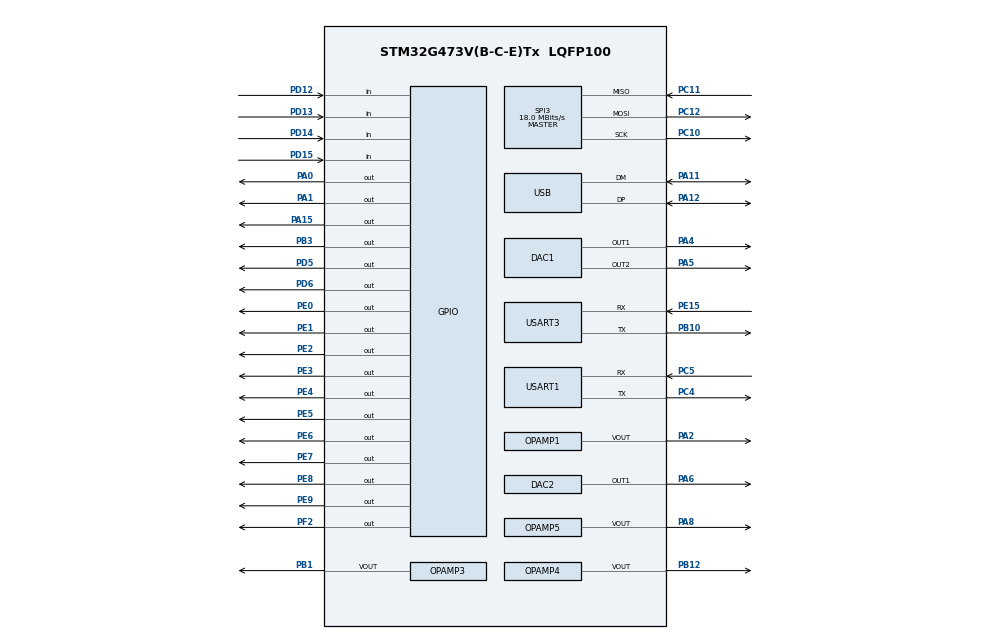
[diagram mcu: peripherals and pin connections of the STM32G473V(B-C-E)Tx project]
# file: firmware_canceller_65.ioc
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DAC1.DAC_Channel-DAC_OUT2=DAC_CHANNEL_2
DAC3.DAC_Channel-DAC_OUT2_Int=DAC_CHANNEL_2
DAC4.DAC_Channel-DAC_OUT2_Int=DAC_CHANNEL_2
Mcu.Family=STM32G4
Mcu.Name=STM32G473V(B-C-E)Tx
Mcu.Package=LQFP100
NVIC.PriorityGroup=NVIC_PRIORITYGROUP_4
NVIC.USB_LP_IRQn=true\:0\:0\:false\:false\:true\:false\:true\:true
PA0.Signal=GPIO_Output
PA1.Signal=GPIO_Output
PA11.Mode=Device
PA11.Signal=USB_DM
PA12.Mode=Device
PA12.Signal=USB_DP
PA13.Mode=Serial_Wire
PA13.Signal=SYS_JTMS-SWDIO
PA14.Mode=Serial_Wire
PA14.Signal=SYS_JTCK-SWCLK
PA15.Signal=GPIO_Output
PA2.Mode=Follower-DAC_OUT2-INP
PA2.Signal=OPAMP1_VOUT
PA4.Signal=COMP_DAC11_group
PA5.Signal=COMP_DAC12_group
PA6.Signal=COMP_DAC21_group
PA8.Mode=Follower-DAC_OUT2-INP
PA8.Signal=OPAMP5_VOUT
PB1.Mode=Follower-DAC_OUT2-INP
PB1.Signal=OPAMP3_VOUT
PB10.Mode=Asynchronous
PB10.Signal=USART3_TX
PB12.Mode=Follower-DAC_OUT2-INP
PB12.Signal=OPAMP4_VOUT
PB3.Signal=GPIO_Output
PC10.Mode=Full_Duplex_Master
PC10.Signal=SPI3_SCK
PC11.Mode=Full_Duplex_Master
PC11.Signal=SPI3_MISO
PC12.Mode=Full_Duplex_Master
PC12.Signal=SPI3_MOSI
PC4.Mode=Asynchronous
PC4.Signal=USART1_TX
PC5.Mode=Asynchronous
PC5.Signal=USART1_RX
PD12.GPIO_PuPd=GPIO_PULLUP
PD12.Signal=GPIO_Input
PD13.GPIO_PuPd=GPIO_PULLUP
PD13.Signal=GPIO_Input
PD14.GPIO_PuPd=GPIO_PULLUP
PD14.Signal=GPIO_Input
PD15.GPIO_PuPd=GPIO_PULLUP
PD15.Signal=GPIO_Input
PD5.Signal=GPIO_Output
PD6.Signal=GPIO_Output
PE0.Signal=GPIO_Output
PE1.Signal=GPIO_Output
PE15.Mode=Asynchronous
PE15.Signal=USART3_RX
PE2.Signal=GPIO_Output
PE3.Signal=GPIO_Output
PE4.Signal=GPIO_Output
PE5.Signal=GPIO_Output
PE6.Signal=GPIO_Output
PE7.Signal=GPIO_Output
PE8.Signal=GPIO_Output
PE9.Signal=GPIO_Output
PF2.Signal=GPIO_Output
ProjectManager.HeapSize=0x200
ProjectManager.StackSize=0x400
ProjectManager.TargetToolchain=MDK-ARM V5.32
RCC.ADC12Freq_Value=144000000
RCC.ADC345Freq_Value=144000000
RCC.AHBFreq_Value=144000000
RCC.APB1Freq_Value=144000000
RCC.APB1TimFreq_Value=144000000
RCC.APB2Freq_Value=144000000
RCC.APB2TimFreq_Value=144000000
RCC.CK48CLockSelection=RCC_USBCLKSOURCE_HSI48
RCC.CortexFreq_Value=144000000
RCC.EXTERNAL_CLOCK_VALUE=12288000
RCC.HCLKFreq_Value=144000000
RCC.HSE_VALUE=12000000
RCC.HSI48_VALUE=48000000
RCC.HSI_VALUE=16000000
RCC.LSE_VALUE=32768
RCC.PLLN=18
RCC.SYSCLKFreq_VALUE=144000000
RCC.SYSCLKSource=RCC_SYSCLKSOURCE_PLLCLK
RCC.USBFreq_Value=48000000
RCC.VCOOutputFreq_Value=288000000
SH.COMP_DAC11_group.0=DAC1_OUT1,DAC_OUT1
SH.COMP_DAC12_group.0=DAC1_OUT2,DAC_OUT2
SH.COMP_DAC21_group.0=DAC2_OUT1,DAC_OUT1
SPI3.BaudRatePrescaler=SPI_BAUDRATEPRESCALER_8
SPI3.CLKPhase=SPI_PHASE_2EDGE
SPI3.CLKPolarity=SPI_POLARITY_LOW
SPI3.CalculateBaudRate=18.0 MBits/s
SPI3.DataSize=SPI_DATASIZE_8BIT
SPI3.Direction=SPI_DIRECTION_2LINES
SPI3.Mode=SPI_MODE_MASTER
SPI3.TIMode=SPI_TIMODE_DISABLE
SPI3.VirtualType=VM_MASTER
USART1.VirtualMode-Asynchronous=VM_ASYNC
USART3.VirtualMode-Asynchronous=VM_ASYNC
USB_DEVICE.CLASS_NAME_FS=CDC
USB_DEVICE.VirtualMode=Cdc
USB_DEVICE.VirtualModeFS=Cdc_FS
VP_DAC3_VS_DACI1.Mode=DAC_OUT1_Int
VP_DAC3_VS_DACI2.Mode=DAC_OUT2_Int
VP_DAC4_VS_DACI1.Mode=DAC_OUT1_Int
VP_DAC4_VS_DACI2.Mode=DAC_OUT2_Int
VP_SYS_VS_DBSignals.Mode=DisableDeadBatterySignals
VP_USB_DEVICE_VS_USB_DEVICE_CDC_FS.Mode=CDC_FS
board=custom

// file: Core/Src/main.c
/* USER CODE BEGIN Header */
/**
  ******************************************************************************
  * @file           : main.c
  * @brief          : Main program body
  ******************************************************************************
  * @attention
  *
  * Copyright (c) 2023 STMicroelectronics.
  * All rights reserved.
  *
  * This software is licensed under terms that can be found in the LICENSE file
  * in the root directory of this software component.
  * If no LICENSE file comes with this software, it is provided AS-IS.
  *
  ******************************************************************************
  */
/* USER CODE END Header */
#include "main.h"
#include "usb_device.h"

/* USER CODE BEGIN Includes */
#include "dacx0508.h"
#include "sic_control.h"
/* USER CODE END Includes */

DAC_HandleTypeDef hdac1;
DAC_HandleTypeDef hdac2;
DAC_HandleTypeDef hdac3;
DAC_HandleTypeDef hdac4;

OPAMP_HandleTypeDef hopamp1;
OPAMP_HandleTypeDef hopamp3;
OPAMP_HandleTypeDef hopamp4;
OPAMP_HandleTypeDef hopamp5;

SPI_HandleTypeDef hspi3;

UART_HandleTypeDef huart1;
UART_HandleTypeDef huart3;

/* USER CODE BEGIN PV */
tap_handle_type_def htap[5];
uint16_t id;
/* USER CODE END PV */

void SystemClock_Config(void);
static void MX_GPIO_Init(void);
static void MX_DAC1_Init(void);
static void MX_DAC2_Init(void);
static void MX_DAC3_Init(void);
static void MX_DAC4_Init(void);
static void MX_OPAMP1_Init(void);
static void MX_OPAMP3_Init(void);
static void MX_OPAMP4_Init(void);
static void MX_OPAMP5_Init(void);
static void MX_SPI3_Init(void);
static void MX_USART1_UART_Init(void);
static void MX_USART3_UART_Init(void);
/* USER CODE BEGIN PFP */
static void sic_init(void);
/* USER CODE END PFP */

int main(void)
{

  /* MCU Configuration--------------------------------------------------------*/

  /* Reset of all peripherals, Initializes the Flash interface and the Systick. */
  HAL_Init();

  /* Configure the system clock */
  SystemClock_Config();

  /* Initialize all configured peripherals */
  MX_GPIO_Init();
  MX_DAC1_Init();
  MX_DAC2_Init();
  MX_DAC3_Init();
  MX_DAC4_Init();
  MX_OPAMP1_Init();
  MX_OPAMP3_Init();
  MX_OPAMP4_Init();
  MX_OPAMP5_Init();
  MX_SPI3_Init();
  MX_USART1_UART_Init();
  MX_USART3_UART_Init();
  MX_USB_Device_Init();
  /* USER CODE BEGIN 2 */
  dacx0508_init(&hspi3);
  sic_init();
  /* USER CODE END 2 */

  /* Infinite loop */
  while (1)
  {

    /* USER CODE BEGIN 3 */
//    if(HAL_GPIO_ReadPin(GPIOD,GPIO_PIN_12))
//      sic_amp_off();
//    else
//      sic_amp_on();

//    if(HAL_GPIO_ReadPin(GPIOD,GPIO_PIN_13))
//      sic_tap_off();
//    else
//      sic_tap_on();

    HAL_GPIO_TogglePin(GPIOA,GPIO_PIN_1);
    HAL_Delay(200);
  }
  /* USER CODE END 3 */
}

void SystemClock_Config(void)
{
  RCC_OscInitTypeDef RCC_OscInitStruct = {0};
  RCC_ClkInitTypeDef RCC_ClkInitStruct = {0};

  /** Configure the main internal regulator output voltage
  */
  HAL_PWREx_ControlVoltageScaling(PWR_REGULATOR_VOLTAGE_SCALE1_BOOST);

  /** Initializes the RCC Oscillators according to the specified parameters
  * in the RCC_OscInitTypeDef structure.
  */
  RCC_OscInitStruct.OscillatorType = RCC_OSCILLATORTYPE_HSI|RCC_OSCILLATORTYPE_HSI48;
  RCC_OscInitStruct.HSIState = RCC_HSI_ON;
  RCC_OscInitStruct.HSICalibrationValue = RCC_HSICALIBRATION_DEFAULT;
  RCC_OscInitStruct.HSI48State = RCC_HSI48_ON;
  RCC_OscInitStruct.PLL.PLLState = RCC_PLL_ON;
  RCC_OscInitStruct.PLL.PLLSource = RCC_PLLSOURCE_HSI;
  RCC_OscInitStruct.PLL.PLLM = RCC_PLLM_DIV1;
  RCC_OscInitStruct.PLL.PLLN = 20;
  RCC_OscInitStruct.PLL.PLLP = RCC_PLLP_DIV2;
  RCC_OscInitStruct.PLL.PLLQ = RCC_PLLQ_DIV2;
  RCC_OscInitStruct.PLL.PLLR = RCC_PLLR_DIV2;
  if (HAL_RCC_OscConfig(&RCC_OscInitStruct) != HAL_OK)
  {
    Error_Handler();
  }

  /** Initializes the CPU, AHB and APB buses clocks
  */
  RCC_ClkInitStruct.ClockType = RCC_CLOCKTYPE_HCLK|RCC_CLOCKTYPE_SYSCLK
                              |RCC_CLOCKTYPE_PCLK1|RCC_CLOCKTYPE_PCLK2;
  RCC_ClkInitStruct.SYSCLKSource = RCC_SYSCLKSOURCE_PLLCLK;
  RCC_ClkInitStruct.AHBCLKDivider = RCC_SYSCLK_DIV1;
  RCC_ClkInitStruct.APB1CLKDivider = RCC_HCLK_DIV1;
  RCC_ClkInitStruct.APB2CLKDivider = RCC_HCLK_DIV1;

  if (HAL_RCC_ClockConfig(&RCC_ClkInitStruct, FLASH_LATENCY_4) != HAL_OK)
  {
    Error_Handler();
  }
}

static void MX_DAC1_Init(void)
{

  DAC_ChannelConfTypeDef sConfig = {0};

  /** DAC Initialization
  */
  hdac1.Instance = DAC1;
  if (HAL_DAC_Init(&hdac1) != HAL_OK)
  {
    Error_Handler();
  }

  /** DAC channel OUT1 config
  */
  sConfig.DAC_HighFrequency = DAC_HIGH_FREQUENCY_INTERFACE_MODE_AUTOMATIC;
  sConfig.DAC_DMADoubleDataMode = DISABLE;
  sConfig.DAC_SignedFormat = DISABLE;
  sConfig.DAC_SampleAndHold = DAC_SAMPLEANDHOLD_DISABLE;
  sConfig.DAC_Trigger = DAC_TRIGGER_NONE;
  sConfig.DAC_Trigger2 = DAC_TRIGGER_NONE;
  sConfig.DAC_OutputBuffer = DAC_OUTPUTBUFFER_ENABLE;
  sConfig.DAC_ConnectOnChipPeripheral = DAC_CHIPCONNECT_EXTERNAL;
  sConfig.DAC_UserTrimming = DAC_TRIMMING_FACTORY;
  if (HAL_DAC_ConfigChannel(&hdac1, &sConfig, DAC_CHANNEL_1) != HAL_OK)
  {
    Error_Handler();
  }

  /** DAC channel OUT2 config
  */
  if (HAL_DAC_ConfigChannel(&hdac1, &sConfig, DAC_CHANNEL_2) != HAL_OK)
  {
    Error_Handler();
  }

}

static void MX_DAC2_Init(void)
{

  DAC_ChannelConfTypeDef sConfig = {0};

  /** DAC Initialization
  */
  hdac2.Instance = DAC2;
  if (HAL_DAC_Init(&hdac2) != HAL_OK)
  {
    Error_Handler();
  }

  /** DAC channel OUT1 config
  */
  sConfig.DAC_HighFrequency = DAC_HIGH_FREQUENCY_INTERFACE_MODE_AUTOMATIC;
  sConfig.DAC_DMADoubleDataMode = DISABLE;
  sConfig.DAC_SignedFormat = DISABLE;
  sConfig.DAC_SampleAndHold = DAC_SAMPLEANDHOLD_DISABLE;
  sConfig.DAC_Trigger = DAC_TRIGGER_NONE;
  sConfig.DAC_Trigger2 = DAC_TRIGGER_NONE;
  sConfig.DAC_OutputBuffer = DAC_OUTPUTBUFFER_ENABLE;
  sConfig.DAC_ConnectOnChipPeripheral = DAC_CHIPCONNECT_EXTERNAL;
  sConfig.DAC_UserTrimming = DAC_TRIMMING_FACTORY;
  if (HAL_DAC_ConfigChannel(&hdac2, &sConfig, DAC_CHANNEL_1) != HAL_OK)
  {
    Error_Handler();
  }

}

static void MX_DAC3_Init(void)
{

  DAC_ChannelConfTypeDef sConfig = {0};

  /** DAC Initialization
  */
  hdac3.Instance = DAC3;
  if (HAL_DAC_Init(&hdac3) != HAL_OK)
  {
    Error_Handler();
  }

  /** DAC channel OUT1 config
  */
  sConfig.DAC_HighFrequency = DAC_HIGH_FREQUENCY_INTERFACE_MODE_AUTOMATIC;
  sConfig.DAC_DMADoubleDataMode = DISABLE;
  sConfig.DAC_SignedFormat = DISABLE;
  sConfig.DAC_SampleAndHold = DAC_SAMPLEANDHOLD_DISABLE;
  sConfig.DAC_Trigger = DAC_TRIGGER_NONE;
  sConfig.DAC_Trigger2 = DAC_TRIGGER_NONE;
  sConfig.DAC_OutputBuffer = DAC_OUTPUTBUFFER_DISABLE;
  sConfig.DAC_ConnectOnChipPeripheral = DAC_CHIPCONNECT_INTERNAL;
  sConfig.DAC_UserTrimming = DAC_TRIMMING_FACTORY;
  if (HAL_DAC_ConfigChannel(&hdac3, &sConfig, DAC_CHANNEL_1) != HAL_OK)
  {
    Error_Handler();
  }

  /** DAC channel OUT2 config
  */
  if (HAL_DAC_ConfigChannel(&hdac3, &sConfig, DAC_CHANNEL_2) != HAL_OK)
  {
    Error_Handler();
  }

}

static void MX_DAC4_Init(void)
{

  DAC_ChannelConfTypeDef sConfig = {0};

  /** DAC Initialization
  */
  hdac4.Instance = DAC4;
  if (HAL_DAC_Init(&hdac4) != HAL_OK)
  {
    Error_Handler();
  }

  /** DAC channel OUT1 config
  */
  sConfig.DAC_HighFrequency = DAC_HIGH_FREQUENCY_INTERFACE_MODE_AUTOMATIC;
  sConfig.DAC_DMADoubleDataMode = DISABLE;
  sConfig.DAC_SignedFormat = DISABLE;
  sConfig.DAC_SampleAndHold = DAC_SAMPLEANDHOLD_DISABLE;
  sConfig.DAC_Trigger = DAC_TRIGGER_NONE;
  sConfig.DAC_Trigger2 = DAC_TRIGGER_NONE;
  sConfig.DAC_OutputBuffer = DAC_OUTPUTBUFFER_DISABLE;
  sConfig.DAC_ConnectOnChipPeripheral = DAC_CHIPCONNECT_INTERNAL;
  sConfig.DAC_UserTrimming = DAC_TRIMMING_FACTORY;
  if (HAL_DAC_ConfigChannel(&hdac4, &sConfig, DAC_CHANNEL_1) != HAL_OK)
  {
    Error_Handler();
  }

  /** DAC channel OUT2 config
  */
  if (HAL_DAC_ConfigChannel(&hdac4, &sConfig, DAC_CHANNEL_2) != HAL_OK)
  {
    Error_Handler();
  }

}

static void MX_OPAMP1_Init(void)
{

  hopamp1.Instance = OPAMP1;
  hopamp1.Init.PowerMode = OPAMP_POWERMODE_NORMALSPEED;
  hopamp1.Init.Mode = OPAMP_FOLLOWER_MODE;
  hopamp1.Init.NonInvertingInput = OPAMP_NONINVERTINGINPUT_DAC;
  hopamp1.Init.InternalOutput = DISABLE;
  hopamp1.Init.TimerControlledMuxmode = OPAMP_TIMERCONTROLLEDMUXMODE_DISABLE;
  hopamp1.Init.UserTrimming = OPAMP_TRIMMING_FACTORY;
  if (HAL_OPAMP_Init(&hopamp1) != HAL_OK)
  {
    Error_Handler();
  }

}

static void MX_OPAMP3_Init(void)
{

  hopamp3.Instance = OPAMP3;
  hopamp3.Init.PowerMode = OPAMP_POWERMODE_NORMALSPEED;
  hopamp3.Init.Mode = OPAMP_FOLLOWER_MODE;
  hopamp3.Init.NonInvertingInput = OPAMP_NONINVERTINGINPUT_DAC;
  hopamp3.Init.InternalOutput = DISABLE;
  hopamp3.Init.TimerControlledMuxmode = OPAMP_TIMERCONTROLLEDMUXMODE_DISABLE;
  hopamp3.Init.UserTrimming = OPAMP_TRIMMING_FACTORY;
  if (HAL_OPAMP_Init(&hopamp3) != HAL_OK)
  {
    Error_Handler();
  }

}

static void MX_OPAMP4_Init(void)
{

  hopamp4.Instance = OPAMP4;
  hopamp4.Init.PowerMode = OPAMP_POWERMODE_NORMALSPEED;
  hopamp4.Init.Mode = OPAMP_FOLLOWER_MODE;
  hopamp4.Init.NonInvertingInput = OPAMP_NONINVERTINGINPUT_DAC;
  hopamp4.Init.InternalOutput = DISABLE;
  hopamp4.Init.TimerControlledMuxmode = OPAMP_TIMERCONTROLLEDMUXMODE_DISABLE;
  hopamp4.Init.UserTrimming = OPAMP_TRIMMING_FACTORY;
  if (HAL_OPAMP_Init(&hopamp4) != HAL_OK)
  {
    Error_Handler();
  }

}

static void MX_OPAMP5_Init(void)
{

  hopamp5.Instance = OPAMP5;
  hopamp5.Init.PowerMode = OPAMP_POWERMODE_NORMALSPEED;
  hopamp5.Init.Mode = OPAMP_FOLLOWER_MODE;
  hopamp5.Init.NonInvertingInput = OPAMP_NONINVERTINGINPUT_DAC;
  hopamp5.Init.InternalOutput = DISABLE;
  hopamp5.Init.TimerControlledMuxmode = OPAMP_TIMERCONTROLLEDMUXMODE_DISABLE;
  hopamp5.Init.UserTrimming = OPAMP_TRIMMING_FACTORY;
  if (HAL_OPAMP_Init(&hopamp5) != HAL_OK)
  {
    Error_Handler();
  }

}

static void MX_SPI3_Init(void)
{

  /* SPI3 parameter configuration*/
  hspi3.Instance = SPI3;
  hspi3.Init.Mode = SPI_MODE_MASTER;
  hspi3.Init.Direction = SPI_DIRECTION_2LINES;
  hspi3.Init.DataSize = SPI_DATASIZE_8BIT;
  hspi3.Init.CLKPolarity = SPI_POLARITY_LOW;
  hspi3.Init.CLKPhase = SPI_PHASE_2EDGE;
  hspi3.Init.NSS = SPI_NSS_SOFT;
  hspi3.Init.BaudRatePrescaler = SPI_BAUDRATEPRESCALER_64;
  hspi3.Init.FirstBit = SPI_FIRSTBIT_MSB;
  hspi3.Init.TIMode = SPI_TIMODE_DISABLE;
  hspi3.Init.CRCCalculation = SPI_CRCCALCULATION_DISABLE;
  hspi3.Init.CRCPolynomial = 7;
  hspi3.Init.CRCLength = SPI_CRC_LENGTH_DATASIZE;
  hspi3.Init.NSSPMode = SPI_NSS_PULSE_DISABLE;
  if (HAL_SPI_Init(&hspi3) != HAL_OK)
  {
    Error_Handler();
  }

}

static void MX_USART1_UART_Init(void)
{

  huart1.Instance = USART1;
  huart1.Init.BaudRate = 115200;
  huart1.Init.WordLength = UART_WORDLENGTH_8B;
  huart1.Init.StopBits = UART_STOPBITS_1;
  huart1.Init.Parity = UART_PARITY_NONE;
  huart1.Init.Mode = UART_MODE_TX_RX;
  huart1.Init.HwFlowCtl = UART_HWCONTROL_NONE;
  huart1.Init.OverSampling = UART_OVERSAMPLING_16;
  huart1.Init.OneBitSampling = UART_ONE_BIT_SAMPLE_DISABLE;
  huart1.Init.ClockPrescaler = UART_PRESCALER_DIV1;
  huart1.AdvancedInit.AdvFeatureInit = UART_ADVFEATURE_NO_INIT;
  if (HAL_UART_Init(&huart1) != HAL_OK)
  {
    Error_Handler();
  }
  if (HAL_UARTEx_SetTxFifoThreshold(&huart1, UART_TXFIFO_THRESHOLD_1_8) != HAL_OK)
  {
    Error_Handler();
  }
  if (HAL_UARTEx_SetRxFifoThreshold(&huart1, UART_RXFIFO_THRESHOLD_1_8) != HAL_OK)
  {
    Error_Handler();
  }
  if (HAL_UARTEx_DisableFifoMode(&huart1) != HAL_OK)
  {
    Error_Handler();
  }

}

static void MX_USART3_UART_Init(void)
{

  huart3.Instance = USART3;
  huart3.Init.BaudRate = 115200;
  huart3.Init.WordLength = UART_WORDLENGTH_8B;
  huart3.Init.StopBits = UART_STOPBITS_1;
  huart3.Init.Parity = UART_PARITY_NONE;
  huart3.Init.Mode = UART_MODE_TX_RX;
  huart3.Init.HwFlowCtl = UART_HWCONTROL_NONE;
  huart3.Init.OverSampling = UART_OVERSAMPLING_16;
  huart3.Init.OneBitSampling = UART_ONE_BIT_SAMPLE_DISABLE;
  huart3.Init.ClockPrescaler = UART_PRESCALER_DIV1;
  huart3.AdvancedInit.AdvFeatureInit = UART_ADVFEATURE_NO_INIT;
  if (HAL_UART_Init(&huart3) != HAL_OK)
  {
    Error_Handler();
  }
  if (HAL_UARTEx_SetTxFifoThreshold(&huart3, UART_TXFIFO_THRESHOLD_1_8) != HAL_OK)
  {
    Error_Handler();
  }
  if (HAL_UARTEx_SetRxFifoThreshold(&huart3, UART_RXFIFO_THRESHOLD_1_8) != HAL_OK)
  {
    Error_Handler();
  }
  if (HAL_UARTEx_DisableFifoMode(&huart3) != HAL_OK)
  {
    Error_Handler();
  }

}

static void MX_GPIO_Init(void)
{
  GPIO_InitTypeDef GPIO_InitStruct = {0};

  /* GPIO Ports Clock Enable */
  __HAL_RCC_GPIOE_CLK_ENABLE();
  __HAL_RCC_GPIOF_CLK_ENABLE();
  __HAL_RCC_GPIOA_CLK_ENABLE();
  __HAL_RCC_GPIOC_CLK_ENABLE();
  __HAL_RCC_GPIOB_CLK_ENABLE();
  __HAL_RCC_GPIOD_CLK_ENABLE();

  /*Configure GPIO pin Output Level */
  HAL_GPIO_WritePin(GPIOE, GPIO_PIN_2|GPIO_PIN_3|GPIO_PIN_4|GPIO_PIN_5
                          |GPIO_PIN_6|GPIO_PIN_7|GPIO_PIN_8|GPIO_PIN_9
                          |GPIO_PIN_0|GPIO_PIN_1, GPIO_PIN_RESET);

  /*Configure GPIO pin Output Level */
  HAL_GPIO_WritePin(GPIOF, GPIO_PIN_2, GPIO_PIN_RESET);

  /*Configure GPIO pin Output Level */
  HAL_GPIO_WritePin(GPIOA, GPIO_PIN_0|GPIO_PIN_1|GPIO_PIN_15, GPIO_PIN_RESET);

  /*Configure GPIO pin Output Level */
  HAL_GPIO_WritePin(GPIOD, GPIO_PIN_5|GPIO_PIN_6, GPIO_PIN_RESET);

  /*Configure GPIO pin Output Level */
  HAL_GPIO_WritePin(GPIOB, GPIO_PIN_3, GPIO_PIN_RESET);

  /*Configure GPIO pins : PE2 PE3 PE4 PE5
                           PE6 PE7 PE8 PE9
                           PE0 PE1 */
  GPIO_InitStruct.Pin = GPIO_PIN_2|GPIO_PIN_3|GPIO_PIN_4|GPIO_PIN_5
                          |GPIO_PIN_6|GPIO_PIN_7|GPIO_PIN_8|GPIO_PIN_9
                          |GPIO_PIN_0|GPIO_PIN_1;
  GPIO_InitStruct.Mode = GPIO_MODE_OUTPUT_PP;
  GPIO_InitStruct.Pull = GPIO_NOPULL;
  GPIO_InitStruct.Speed = GPIO_SPEED_FREQ_LOW;
  HAL_GPIO_Init(GPIOE, &GPIO_InitStruct);

  /*Configure GPIO pin : PF2 */
  GPIO_InitStruct.Pin = GPIO_PIN_2;
  GPIO_InitStruct.Mode = GPIO_MODE_OUTPUT_PP;
  GPIO_InitStruct.Pull = GPIO_NOPULL;
  GPIO_InitStruct.Speed = GPIO_SPEED_FREQ_LOW;
  HAL_GPIO_Init(GPIOF, &GPIO_InitStruct);

  /*Configure GPIO pins : PA0 PA1 PA15 */
  GPIO_InitStruct.Pin = GPIO_PIN_0|GPIO_PIN_1|GPIO_PIN_15;
  GPIO_InitStruct.Mode = GPIO_MODE_OUTPUT_PP;
  GPIO_InitStruct.Pull = GPIO_NOPULL;
  GPIO_InitStruct.Speed = GPIO_SPEED_FREQ_LOW;
  HAL_GPIO_Init(GPIOA, &GPIO_InitStruct);

  /*Configure GPIO pins : PD12 PD13 PD14 PD15 */
  GPIO_InitStruct.Pin = GPIO_PIN_12|GPIO_PIN_13|GPIO_PIN_14|GPIO_PIN_15;
  GPIO_InitStruct.Mode = GPIO_MODE_INPUT;
  GPIO_InitStruct.Pull = GPIO_PULLUP;
  HAL_GPIO_Init(GPIOD, &GPIO_InitStruct);

  /*Configure GPIO pins : PD5 PD6 */
  GPIO_InitStruct.Pin = GPIO_PIN_5|GPIO_PIN_6;
  GPIO_InitStruct.Mode = GPIO_MODE_OUTPUT_PP;
  GPIO_InitStruct.Pull = GPIO_NOPULL;
  GPIO_InitStruct.Speed = GPIO_SPEED_FREQ_LOW;
  HAL_GPIO_Init(GPIOD, &GPIO_InitStruct);

  /*Configure GPIO pin : PB3 */
  GPIO_InitStruct.Pin = GPIO_PIN_3;
  GPIO_InitStruct.Mode = GPIO_MODE_OUTPUT_PP;
  GPIO_InitStruct.Pull = GPIO_NOPULL;
  GPIO_InitStruct.Speed = GPIO_SPEED_FREQ_LOW;
  HAL_GPIO_Init(GPIOB, &GPIO_InitStruct);

}

/* USER CODE BEGIN 4 */
/**
  * @brief SIC Initialization Function
  * @param None
  * @retval None
  */
static void sic_init(void)
{
  sic_off();

  htap[0].att_dac_handle=&hdac3;
  htap[0].att_dac_channel=DAC_CHANNEL_1;
  htap[0].att_slope=1;
  htap[0].att_data=0;
  htap[0].ps_dac_spi_handle=&hspi3;
  htap[0].ps_dac_channel=0;
  htap[0].ps_data=0;

  if(htap[0].att_slope==1)
    HAL_GPIO_WritePin(GPIOE,GPIO_PIN_1,GPIO_PIN_SET);
  else
    HAL_GPIO_WritePin(GPIOE,GPIO_PIN_1,GPIO_PIN_RESET);

  HAL_OPAMP_Start(&hopamp1);
  HAL_DAC_Start(&hdac3,DAC_CHANNEL_1);

  htap[1].att_dac_handle=&hdac4;
  htap[1].att_dac_channel=DAC_CHANNEL_1;
  htap[1].att_slope=1;
  htap[1].att_data=0;
  htap[1].ps_dac_spi_handle=&hspi3;
  htap[1].ps_dac_channel=1;
  htap[1].ps_data=0;

  if(htap[1].att_slope==1)
    HAL_GPIO_WritePin(GPIOE,GPIO_PIN_3,GPIO_PIN_SET);
  else
    HAL_GPIO_WritePin(GPIOE,GPIO_PIN_3,GPIO_PIN_RESET);

  HAL_OPAMP_Start(&hopamp4);
  HAL_DAC_Start(&hdac4,DAC_CHANNEL_1);

  htap[2].att_dac_handle=&hdac4;
  htap[2].att_dac_channel=DAC_CHANNEL_2;
  htap[2].att_slope=1;
  htap[2].att_data=0;
  htap[2].ps_dac_spi_handle=&hspi3;
  htap[2].ps_dac_channel=2;
  htap[2].ps_data=0;

  if(htap[2].att_slope==1)
    HAL_GPIO_WritePin(GPIOE,GPIO_PIN_5,GPIO_PIN_SET);
  else
    HAL_GPIO_WritePin(GPIOE,GPIO_PIN_5,GPIO_PIN_RESET);

  HAL_OPAMP_Start(&hopamp5);
  HAL_DAC_Start(&hdac4,DAC_CHANNEL_2);

  htap[3].att_dac_handle=&hdac3;
  htap[3].att_dac_channel=DAC_CHANNEL_2;
  htap[3].att_slope=1;
  htap[3].att_data=0;
  htap[3].ps_dac_spi_handle=&hspi3;
  htap[3].ps_dac_channel=3;
  htap[3].ps_data=0;

  if(htap[3].att_slope==1)
    HAL_GPIO_WritePin(GPIOE,GPIO_PIN_7,GPIO_PIN_SET);
  else
    HAL_GPIO_WritePin(GPIOE,GPIO_PIN_7,GPIO_PIN_RESET);

  HAL_OPAMP_Start(&hopamp3);
  HAL_DAC_Start(&hdac3,DAC_CHANNEL_2);

  htap[4].att_dac_handle=&hdac1;
  htap[4].att_dac_channel=DAC_CHANNEL_2;
  htap[4].att_slope=1;
  htap[4].att_data=0;
  htap[4].ps_dac_spi_handle=&hspi3;
  htap[4].ps_dac_channel=4;
  htap[4].ps_data=0;

  if(htap[4].att_slope==1)
    HAL_GPIO_WritePin(GPIOE,GPIO_PIN_9,GPIO_PIN_SET);
  else
    HAL_GPIO_WritePin(GPIOE,GPIO_PIN_9,GPIO_PIN_RESET);

  HAL_DAC_Start(&hdac1,DAC_CHANNEL_2);

  sic_tap_on();
}
/* USER CODE END 4 */

void Error_Handler(void)
{
  __disable_irq();
  while (1)
  {
  }
}
